VERSION 5.7 ;
  NOWIREEXTENSIONATPIN ON ;
  DIVIDERCHAR "/" ;
  BUSBITCHARS "[]" ;
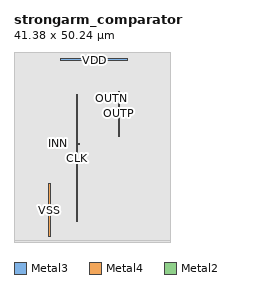
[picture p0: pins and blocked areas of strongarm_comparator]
MACRO strongarm_comparator
  CLASS BLOCK ;
  FOREIGN strongarm_comparator ;
  ORIGIN 20.800 4.240 ;
  SIZE 41.380 BY 50.240 ;
  PIN OUTN
    ANTENNAGATEAREA 2.650000 ;
    ANTENNADIFFAREA 4.140000 ;
    PORT
      LAYER Metal3 ;
        RECT 4.840 33.640 5.120 33.920 ;
      LAYER Metal4 ;
        RECT 4.840 33.640 5.120 33.920 ;
    END
  END OUTN
  PIN OUTP
    ANTENNAGATEAREA 2.650000 ;
    ANTENNADIFFAREA 4.140000 ;
    PORT
      LAYER Metal4 ;
        RECT 6.880 23.720 7.160 35.680 ;
    END
  END OUTP
  PIN CLK
    ANTENNAGATEAREA 6.950000 ;
    PORT
      LAYER Metal4 ;
        RECT -4.340 1.280 -4.060 34.660 ;
    END
  END CLK
  PIN INN
    ANTENNAGATEAREA 2.100000 ;
    PORT
      LAYER Metal2 ;
        RECT -9.280 21.650 -9.000 21.930 ;
    END
  END INN
  PIN INP
    ANTENNAGATEAREA 2.100000 ;
    PORT
      LAYER Metal2 ;
        RECT -3.720 21.650 -3.440 21.930 ;
    END
  END INP
  PIN VSS
    USE GROUND ;
    PORT
      LAYER Metal4 ;
        RECT -11.620 -2.800 -11.060 11.200 ;
    END
  END VSS
  PIN VDD
    USE POWER ;
    PORT
      LAYER Metal3 ;
        RECT -8.560 43.700 9.340 44.260 ;
    END
  END VDD
  OBS
      LAYER Nwell ;
        RECT -17.580 0.000 17.580 42.370 ;
      LAYER Metal1 ;
        RECT -17.350 0.210 18.490 42.160 ;
      LAYER Metal2 ;
        RECT -17.350 22.230 18.490 42.160 ;
        RECT -17.350 21.350 -9.580 22.230 ;
        RECT -8.700 21.350 -4.020 22.230 ;
        RECT -3.140 21.350 18.490 22.230 ;
        RECT -17.350 0.210 18.490 21.350 ;
      LAYER Metal3 ;
        RECT -20.800 44.560 20.560 45.280 ;
        RECT -20.800 43.400 -8.860 44.560 ;
        RECT 9.640 43.400 20.560 44.560 ;
        RECT -20.800 -4.240 20.560 43.400 ;
      LAYER Metal4 ;
        RECT -20.770 35.980 20.530 45.250 ;
        RECT -20.770 34.960 6.580 35.980 ;
        RECT -20.770 11.500 -4.640 34.960 ;
        RECT -20.770 -3.100 -11.920 11.500 ;
        RECT -10.760 0.980 -4.640 11.500 ;
        RECT -3.760 34.220 6.580 34.960 ;
        RECT -3.760 33.340 4.540 34.220 ;
        RECT 5.420 33.340 6.580 34.220 ;
        RECT -3.760 23.420 6.580 33.340 ;
        RECT 7.460 23.420 20.530 35.980 ;
        RECT -3.760 0.980 20.530 23.420 ;
        RECT -10.760 -3.100 20.530 0.980 ;
        RECT -20.770 -3.220 20.530 -3.100 ;
      LAYER Metal5 ;
        RECT -20.770 -3.940 20.580 46.000 ;
  END
END strongarm_comparator
END LIBRARY

